VERSION 5.8 ;
BUSBITCHARS "[]" ;
DIVIDERCHAR "/" ;
UNITS
    DATABASE MICRONS 1000 ;
END UNITS

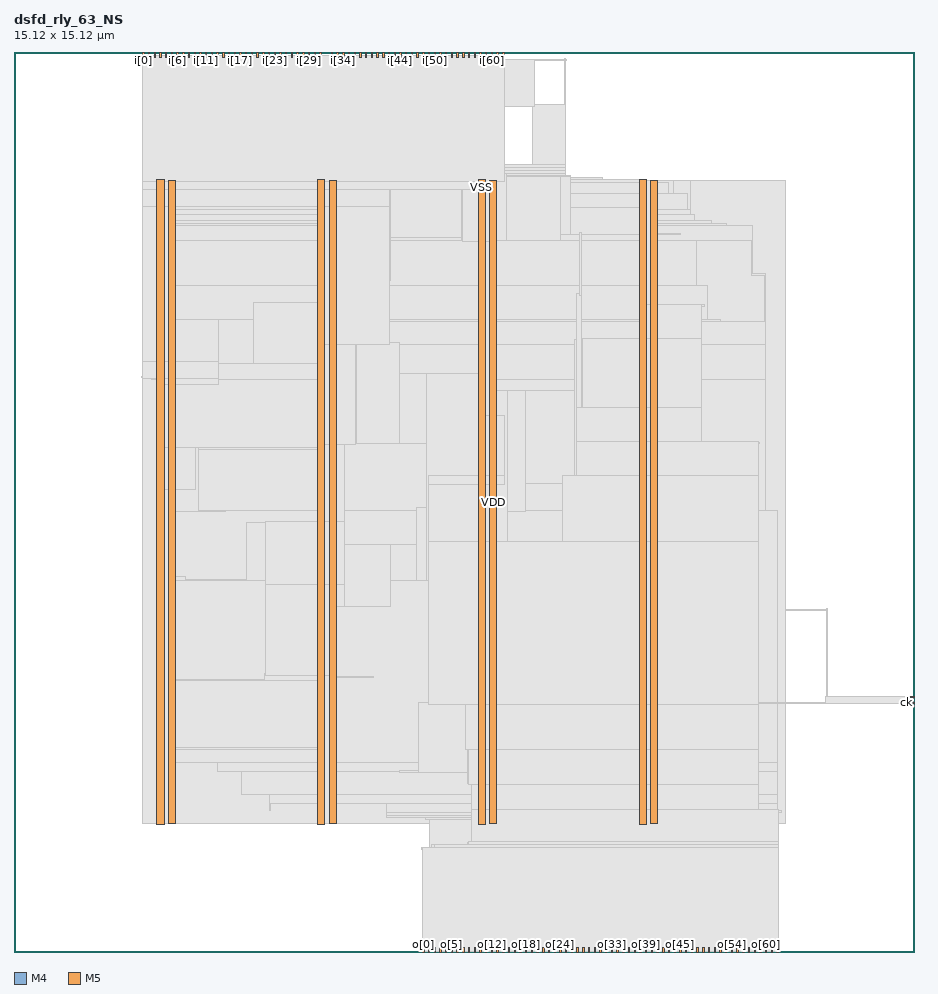
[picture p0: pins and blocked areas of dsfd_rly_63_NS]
MACRO dsfd_rly_63_NS
  FOREIGN dsfd_rly_63_NS 0 0 ;
  CLASS BLOCK ;
  SIZE 15.12 BY 15.12 ;
  PIN ck
    DIRECTION INPUT ;
    USE SIGNAL ;
    PORT
      LAYER M4 ;
        RECT  15.036 4.176 15.12 4.2 ;
    END
  END ck
  PIN i[0]
    DIRECTION INPUT ;
    USE SIGNAL ;
    PORT
      LAYER M5 ;
        RECT  2.16 15.036 2.184 15.12 ;
    END
  END i[0]
  PIN i[10]
    DIRECTION INPUT ;
    USE SIGNAL ;
    PORT
      LAYER M5 ;
        RECT  3.12 15.036 3.144 15.12 ;
    END
  END i[10]
  PIN i[11]
    DIRECTION INPUT ;
    USE SIGNAL ;
    PORT
      LAYER M5 ;
        RECT  3.216 15.036 3.24 15.12 ;
    END
  END i[11]
  PIN i[12]
    DIRECTION INPUT ;
    USE SIGNAL ;
    PORT
      LAYER M5 ;
        RECT  3.312 15.036 3.336 15.12 ;
    END
  END i[12]
  PIN i[13]
    DIRECTION INPUT ;
    USE SIGNAL ;
    PORT
      LAYER M5 ;
        RECT  3.408 15.036 3.432 15.12 ;
    END
  END i[13]
  PIN i[14]
    DIRECTION INPUT ;
    USE SIGNAL ;
    PORT
      LAYER M5 ;
        RECT  3.504 15.036 3.528 15.12 ;
    END
  END i[14]
  PIN i[15]
    DIRECTION INPUT ;
    USE SIGNAL ;
    PORT
      LAYER M5 ;
        RECT  3.6 15.036 3.624 15.12 ;
    END
  END i[15]
  PIN i[16]
    DIRECTION INPUT ;
    USE SIGNAL ;
    PORT
      LAYER M5 ;
        RECT  3.696 15.036 3.72 15.12 ;
    END
  END i[16]
  PIN i[17]
    DIRECTION INPUT ;
    USE SIGNAL ;
    PORT
      LAYER M5 ;
        RECT  3.792 15.036 3.816 15.12 ;
    END
  END i[17]
  PIN i[18]
    DIRECTION INPUT ;
    USE SIGNAL ;
    PORT
      LAYER M5 ;
        RECT  3.888 15.036 3.912 15.12 ;
    END
  END i[18]
  PIN i[19]
    DIRECTION INPUT ;
    USE SIGNAL ;
    PORT
      LAYER M5 ;
        RECT  3.984 15.036 4.008 15.12 ;
    END
  END i[19]
  PIN i[1]
    DIRECTION INPUT ;
    USE SIGNAL ;
    PORT
      LAYER M5 ;
        RECT  2.256 15.036 2.28 15.12 ;
    END
  END i[1]
  PIN i[20]
    DIRECTION INPUT ;
    USE SIGNAL ;
    PORT
      LAYER M5 ;
        RECT  4.08 15.036 4.104 15.12 ;
    END
  END i[20]
  PIN i[21]
    DIRECTION INPUT ;
    USE SIGNAL ;
    PORT
      LAYER M5 ;
        RECT  4.176 15.036 4.2 15.12 ;
    END
  END i[21]
  PIN i[22]
    DIRECTION INPUT ;
    USE SIGNAL ;
    PORT
      LAYER M5 ;
        RECT  4.272 15.036 4.296 15.12 ;
    END
  END i[22]
  PIN i[23]
    DIRECTION INPUT ;
    USE SIGNAL ;
    PORT
      LAYER M5 ;
        RECT  4.368 15.036 4.392 15.12 ;
    END
  END i[23]
  PIN i[24]
    DIRECTION INPUT ;
    USE SIGNAL ;
    PORT
      LAYER M5 ;
        RECT  4.464 15.036 4.488 15.12 ;
    END
  END i[24]
  PIN i[25]
    DIRECTION INPUT ;
    USE SIGNAL ;
    PORT
      LAYER M5 ;
        RECT  4.56 15.036 4.584 15.12 ;
    END
  END i[25]
  PIN i[26]
    DIRECTION INPUT ;
    USE SIGNAL ;
    PORT
      LAYER M5 ;
        RECT  4.656 15.036 4.68 15.12 ;
    END
  END i[26]
  PIN i[27]
    DIRECTION INPUT ;
    USE SIGNAL ;
    PORT
      LAYER M5 ;
        RECT  4.752 15.036 4.776 15.12 ;
    END
  END i[27]
  PIN i[28]
    DIRECTION INPUT ;
    USE SIGNAL ;
    PORT
      LAYER M5 ;
        RECT  4.848 15.036 4.872 15.12 ;
    END
  END i[28]
  PIN i[29]
    DIRECTION INPUT ;
    USE SIGNAL ;
    PORT
      LAYER M5 ;
        RECT  4.944 15.036 4.968 15.12 ;
    END
  END i[29]
  PIN i[2]
    DIRECTION INPUT ;
    USE SIGNAL ;
    PORT
      LAYER M5 ;
        RECT  2.352 15.036 2.376 15.12 ;
    END
  END i[2]
  PIN i[30]
    DIRECTION INPUT ;
    USE SIGNAL ;
    PORT
      LAYER M5 ;
        RECT  5.04 15.036 5.064 15.12 ;
    END
  END i[30]
  PIN i[31]
    DIRECTION INPUT ;
    USE SIGNAL ;
    PORT
      LAYER M5 ;
        RECT  5.136 15.036 5.16 15.12 ;
    END
  END i[31]
  PIN i[32]
    DIRECTION INPUT ;
    USE SIGNAL ;
    PORT
      LAYER M5 ;
        RECT  5.328 15.036 5.352 15.12 ;
    END
  END i[32]
  PIN i[33]
    DIRECTION INPUT ;
    USE SIGNAL ;
    PORT
      LAYER M5 ;
        RECT  5.424 15.036 5.448 15.12 ;
    END
  END i[33]
  PIN i[34]
    DIRECTION INPUT ;
    USE SIGNAL ;
    PORT
      LAYER M5 ;
        RECT  5.52 15.036 5.544 15.12 ;
    END
  END i[34]
  PIN i[35]
    DIRECTION INPUT ;
    USE SIGNAL ;
    PORT
      LAYER M5 ;
        RECT  5.616 15.036 5.64 15.12 ;
    END
  END i[35]
  PIN i[36]
    DIRECTION INPUT ;
    USE SIGNAL ;
    PORT
      LAYER M5 ;
        RECT  5.712 15.036 5.736 15.12 ;
    END
  END i[36]
  PIN i[37]
    DIRECTION INPUT ;
    USE SIGNAL ;
    PORT
      LAYER M5 ;
        RECT  5.808 15.036 5.832 15.12 ;
    END
  END i[37]
  PIN i[38]
    DIRECTION INPUT ;
    USE SIGNAL ;
    PORT
      LAYER M5 ;
        RECT  5.904 15.036 5.928 15.12 ;
    END
  END i[38]
  PIN i[39]
    DIRECTION INPUT ;
    USE SIGNAL ;
    PORT
      LAYER M5 ;
        RECT  6 15.036 6.024 15.12 ;
    END
  END i[39]
  PIN i[3]
    DIRECTION INPUT ;
    USE SIGNAL ;
    PORT
      LAYER M5 ;
        RECT  2.448 15.036 2.472 15.12 ;
    END
  END i[3]
  PIN i[40]
    DIRECTION INPUT ;
    USE SIGNAL ;
    PORT
      LAYER M5 ;
        RECT  6.096 15.036 6.12 15.12 ;
    END
  END i[40]
  PIN i[41]
    DIRECTION INPUT ;
    USE SIGNAL ;
    PORT
      LAYER M5 ;
        RECT  6.192 15.036 6.216 15.12 ;
    END
  END i[41]
  PIN i[42]
    DIRECTION INPUT ;
    USE SIGNAL ;
    PORT
      LAYER M5 ;
        RECT  6.288 15.036 6.312 15.12 ;
    END
  END i[42]
  PIN i[43]
    DIRECTION INPUT ;
    USE SIGNAL ;
    PORT
      LAYER M5 ;
        RECT  6.384 15.036 6.408 15.12 ;
    END
  END i[43]
  PIN i[44]
    DIRECTION INPUT ;
    USE SIGNAL ;
    PORT
      LAYER M5 ;
        RECT  6.48 15.036 6.504 15.12 ;
    END
  END i[44]
  PIN i[45]
    DIRECTION INPUT ;
    USE SIGNAL ;
    PORT
      LAYER M5 ;
        RECT  6.576 15.036 6.6 15.12 ;
    END
  END i[45]
  PIN i[46]
    DIRECTION INPUT ;
    USE SIGNAL ;
    PORT
      LAYER M5 ;
        RECT  6.672 15.036 6.696 15.12 ;
    END
  END i[46]
  PIN i[47]
    DIRECTION INPUT ;
    USE SIGNAL ;
    PORT
      LAYER M5 ;
        RECT  6.768 15.036 6.792 15.12 ;
    END
  END i[47]
  PIN i[48]
    DIRECTION INPUT ;
    USE SIGNAL ;
    PORT
      LAYER M5 ;
        RECT  6.864 15.036 6.888 15.12 ;
    END
  END i[48]
  PIN i[49]
    DIRECTION INPUT ;
    USE SIGNAL ;
    PORT
      LAYER M5 ;
        RECT  6.96 15.036 6.984 15.12 ;
    END
  END i[49]
  PIN i[4]
    DIRECTION INPUT ;
    USE SIGNAL ;
    PORT
      LAYER M5 ;
        RECT  2.544 15.036 2.568 15.12 ;
    END
  END i[4]
  PIN i[50]
    DIRECTION INPUT ;
    USE SIGNAL ;
    PORT
      LAYER M5 ;
        RECT  7.056 15.036 7.08 15.12 ;
    END
  END i[50]
  PIN i[51]
    DIRECTION INPUT ;
    USE SIGNAL ;
    PORT
      LAYER M5 ;
        RECT  7.152 15.036 7.176 15.12 ;
    END
  END i[51]
  PIN i[52]
    DIRECTION INPUT ;
    USE SIGNAL ;
    PORT
      LAYER M5 ;
        RECT  7.248 15.036 7.272 15.12 ;
    END
  END i[52]
  PIN i[53]
    DIRECTION INPUT ;
    USE SIGNAL ;
    PORT
      LAYER M5 ;
        RECT  7.344 15.036 7.368 15.12 ;
    END
  END i[53]
  PIN i[54]
    DIRECTION INPUT ;
    USE SIGNAL ;
    PORT
      LAYER M5 ;
        RECT  7.44 15.036 7.464 15.12 ;
    END
  END i[54]
  PIN i[55]
    DIRECTION INPUT ;
    USE SIGNAL ;
    PORT
      LAYER M5 ;
        RECT  7.536 15.036 7.56 15.12 ;
    END
  END i[55]
  PIN i[56]
    DIRECTION INPUT ;
    USE SIGNAL ;
    PORT
      LAYER M5 ;
        RECT  7.632 15.036 7.656 15.12 ;
    END
  END i[56]
  PIN i[57]
    DIRECTION INPUT ;
    USE SIGNAL ;
    PORT
      LAYER M5 ;
        RECT  7.728 15.036 7.752 15.12 ;
    END
  END i[57]
  PIN i[58]
    DIRECTION INPUT ;
    USE SIGNAL ;
    PORT
      LAYER M5 ;
        RECT  7.824 15.036 7.848 15.12 ;
    END
  END i[58]
  PIN i[59]
    DIRECTION INPUT ;
    USE SIGNAL ;
    PORT
      LAYER M5 ;
        RECT  7.92 15.036 7.944 15.12 ;
    END
  END i[59]
  PIN i[5]
    DIRECTION INPUT ;
    USE SIGNAL ;
    PORT
      LAYER M5 ;
        RECT  2.64 15.036 2.664 15.12 ;
    END
  END i[5]
  PIN i[60]
    DIRECTION INPUT ;
    USE SIGNAL ;
    PORT
      LAYER M5 ;
        RECT  8.016 15.036 8.04 15.12 ;
    END
  END i[60]
  PIN i[61]
    DIRECTION INPUT ;
    USE SIGNAL ;
    PORT
      LAYER M5 ;
        RECT  8.112 15.036 8.136 15.12 ;
    END
  END i[61]
  PIN i[62]
    DIRECTION INPUT ;
    USE SIGNAL ;
    PORT
      LAYER M5 ;
        RECT  8.208 15.036 8.232 15.12 ;
    END
  END i[62]
  PIN i[6]
    DIRECTION INPUT ;
    USE SIGNAL ;
    PORT
      LAYER M5 ;
        RECT  2.736 15.036 2.76 15.12 ;
    END
  END i[6]
  PIN i[7]
    DIRECTION INPUT ;
    USE SIGNAL ;
    PORT
      LAYER M5 ;
        RECT  2.832 15.036 2.856 15.12 ;
    END
  END i[7]
  PIN i[8]
    DIRECTION INPUT ;
    USE SIGNAL ;
    PORT
      LAYER M5 ;
        RECT  2.928 15.036 2.952 15.12 ;
    END
  END i[8]
  PIN i[9]
    DIRECTION INPUT ;
    USE SIGNAL ;
    PORT
      LAYER M5 ;
        RECT  3.024 15.036 3.048 15.12 ;
    END
  END i[9]
  PIN o[0]
    DIRECTION OUTPUT ;
    USE SIGNAL ;
    PORT
      LAYER M5 ;
        RECT  6.864 0 6.888 0.084 ;
    END
  END o[0]
  PIN o[10]
    DIRECTION OUTPUT ;
    USE SIGNAL ;
    PORT
      LAYER M5 ;
        RECT  7.824 0 7.848 0.084 ;
    END
  END o[10]
  PIN o[11]
    DIRECTION OUTPUT ;
    USE SIGNAL ;
    PORT
      LAYER M5 ;
        RECT  7.92 0 7.944 0.084 ;
    END
  END o[11]
  PIN o[12]
    DIRECTION OUTPUT ;
    USE SIGNAL ;
    PORT
      LAYER M5 ;
        RECT  8.016 0 8.04 0.084 ;
    END
  END o[12]
  PIN o[13]
    DIRECTION OUTPUT ;
    USE SIGNAL ;
    PORT
      LAYER M5 ;
        RECT  8.112 0 8.136 0.084 ;
    END
  END o[13]
  PIN o[14]
    DIRECTION OUTPUT ;
    USE SIGNAL ;
    PORT
      LAYER M5 ;
        RECT  8.208 0 8.232 0.084 ;
    END
  END o[14]
  PIN o[15]
    DIRECTION OUTPUT ;
    USE SIGNAL ;
    PORT
      LAYER M5 ;
        RECT  8.304 0 8.328 0.084 ;
    END
  END o[15]
  PIN o[16]
    DIRECTION OUTPUT ;
    USE SIGNAL ;
    PORT
      LAYER M5 ;
        RECT  8.4 0 8.424 0.084 ;
    END
  END o[16]
  PIN o[17]
    DIRECTION OUTPUT ;
    USE SIGNAL ;
    PORT
      LAYER M5 ;
        RECT  8.496 0 8.52 0.084 ;
    END
  END o[17]
  PIN o[18]
    DIRECTION OUTPUT ;
    USE SIGNAL ;
    PORT
      LAYER M5 ;
        RECT  8.592 0 8.616 0.084 ;
    END
  END o[18]
  PIN o[19]
    DIRECTION OUTPUT ;
    USE SIGNAL ;
    PORT
      LAYER M5 ;
        RECT  8.688 0 8.712 0.084 ;
    END
  END o[19]
  PIN o[1]
    DIRECTION OUTPUT ;
    USE SIGNAL ;
    PORT
      LAYER M5 ;
        RECT  6.96 0 6.984 0.084 ;
    END
  END o[1]
  PIN o[20]
    DIRECTION OUTPUT ;
    USE SIGNAL ;
    PORT
      LAYER M5 ;
        RECT  8.784 0 8.808 0.084 ;
    END
  END o[20]
  PIN o[21]
    DIRECTION OUTPUT ;
    USE SIGNAL ;
    PORT
      LAYER M5 ;
        RECT  8.88 0 8.904 0.084 ;
    END
  END o[21]
  PIN o[22]
    DIRECTION OUTPUT ;
    USE SIGNAL ;
    PORT
      LAYER M5 ;
        RECT  8.976 0 9 0.084 ;
    END
  END o[22]
  PIN o[23]
    DIRECTION OUTPUT ;
    USE SIGNAL ;
    PORT
      LAYER M5 ;
        RECT  9.072 0 9.096 0.084 ;
    END
  END o[23]
  PIN o[24]
    DIRECTION OUTPUT ;
    USE SIGNAL ;
    PORT
      LAYER M5 ;
        RECT  9.168 0 9.192 0.084 ;
    END
  END o[24]
  PIN o[25]
    DIRECTION OUTPUT ;
    USE SIGNAL ;
    PORT
      LAYER M5 ;
        RECT  9.264 0 9.288 0.084 ;
    END
  END o[25]
  PIN o[26]
    DIRECTION OUTPUT ;
    USE SIGNAL ;
    PORT
      LAYER M5 ;
        RECT  9.36 0 9.384 0.084 ;
    END
  END o[26]
  PIN o[27]
    DIRECTION OUTPUT ;
    USE SIGNAL ;
    PORT
      LAYER M5 ;
        RECT  9.456 0 9.48 0.084 ;
    END
  END o[27]
  PIN o[28]
    DIRECTION OUTPUT ;
    USE SIGNAL ;
    PORT
      LAYER M5 ;
        RECT  9.552 0 9.576 0.084 ;
    END
  END o[28]
  PIN o[29]
    DIRECTION OUTPUT ;
    USE SIGNAL ;
    PORT
      LAYER M5 ;
        RECT  9.648 0 9.672 0.084 ;
    END
  END o[29]
  PIN o[2]
    DIRECTION OUTPUT ;
    USE SIGNAL ;
    PORT
      LAYER M5 ;
        RECT  7.056 0 7.08 0.084 ;
    END
  END o[2]
  PIN o[30]
    DIRECTION OUTPUT ;
    USE SIGNAL ;
    PORT
      LAYER M5 ;
        RECT  9.744 0 9.768 0.084 ;
    END
  END o[30]
  PIN o[31]
    DIRECTION OUTPUT ;
    USE SIGNAL ;
    PORT
      LAYER M5 ;
        RECT  9.84 0 9.864 0.084 ;
    END
  END o[31]
  PIN o[32]
    DIRECTION OUTPUT ;
    USE SIGNAL ;
    PORT
      LAYER M5 ;
        RECT  9.936 0 9.96 0.084 ;
    END
  END o[32]
  PIN o[33]
    DIRECTION OUTPUT ;
    USE SIGNAL ;
    PORT
      LAYER M5 ;
        RECT  10.032 0 10.056 0.084 ;
    END
  END o[33]
  PIN o[34]
    DIRECTION OUTPUT ;
    USE SIGNAL ;
    PORT
      LAYER M5 ;
        RECT  10.128 0 10.152 0.084 ;
    END
  END o[34]
  PIN o[35]
    DIRECTION OUTPUT ;
    USE SIGNAL ;
    PORT
      LAYER M5 ;
        RECT  10.224 0 10.248 0.084 ;
    END
  END o[35]
  PIN o[36]
    DIRECTION OUTPUT ;
    USE SIGNAL ;
    PORT
      LAYER M5 ;
        RECT  10.32 0 10.344 0.084 ;
    END
  END o[36]
  PIN o[37]
    DIRECTION OUTPUT ;
    USE SIGNAL ;
    PORT
      LAYER M5 ;
        RECT  10.416 0 10.44 0.084 ;
    END
  END o[37]
  PIN o[38]
    DIRECTION OUTPUT ;
    USE SIGNAL ;
    PORT
      LAYER M5 ;
        RECT  10.512 0 10.536 0.084 ;
    END
  END o[38]
  PIN o[39]
    DIRECTION OUTPUT ;
    USE SIGNAL ;
    PORT
      LAYER M5 ;
        RECT  10.608 0 10.632 0.084 ;
    END
  END o[39]
  PIN o[3]
    DIRECTION OUTPUT ;
    USE SIGNAL ;
    PORT
      LAYER M5 ;
        RECT  7.152 0 7.176 0.084 ;
    END
  END o[3]
  PIN o[40]
    DIRECTION OUTPUT ;
    USE SIGNAL ;
    PORT
      LAYER M5 ;
        RECT  10.704 0 10.728 0.084 ;
    END
  END o[40]
  PIN o[41]
    DIRECTION OUTPUT ;
    USE SIGNAL ;
    PORT
      LAYER M5 ;
        RECT  10.8 0 10.824 0.084 ;
    END
  END o[41]
  PIN o[42]
    DIRECTION OUTPUT ;
    USE SIGNAL ;
    PORT
      LAYER M5 ;
        RECT  10.896 0 10.92 0.084 ;
    END
  END o[42]
  PIN o[43]
    DIRECTION OUTPUT ;
    USE SIGNAL ;
    PORT
      LAYER M5 ;
        RECT  10.992 0 11.016 0.084 ;
    END
  END o[43]
  PIN o[44]
    DIRECTION OUTPUT ;
    USE SIGNAL ;
    PORT
      LAYER M5 ;
        RECT  11.088 0 11.112 0.084 ;
    END
  END o[44]
  PIN o[45]
    DIRECTION OUTPUT ;
    USE SIGNAL ;
    PORT
      LAYER M5 ;
        RECT  11.184 0 11.208 0.084 ;
    END
  END o[45]
  PIN o[46]
    DIRECTION OUTPUT ;
    USE SIGNAL ;
    PORT
      LAYER M5 ;
        RECT  11.28 0 11.304 0.084 ;
    END
  END o[46]
  PIN o[47]
    DIRECTION OUTPUT ;
    USE SIGNAL ;
    PORT
      LAYER M5 ;
        RECT  11.376 0 11.4 0.084 ;
    END
  END o[47]
  PIN o[48]
    DIRECTION OUTPUT ;
    USE SIGNAL ;
    PORT
      LAYER M5 ;
        RECT  11.472 0 11.496 0.084 ;
    END
  END o[48]
  PIN o[49]
    DIRECTION OUTPUT ;
    USE SIGNAL ;
    PORT
      LAYER M5 ;
        RECT  11.568 0 11.592 0.084 ;
    END
  END o[49]
  PIN o[4]
    DIRECTION OUTPUT ;
    USE SIGNAL ;
    PORT
      LAYER M5 ;
        RECT  7.248 0 7.272 0.084 ;
    END
  END o[4]
  PIN o[50]
    DIRECTION OUTPUT ;
    USE SIGNAL ;
    PORT
      LAYER M5 ;
        RECT  11.664 0 11.688 0.084 ;
    END
  END o[50]
  PIN o[51]
    DIRECTION OUTPUT ;
    USE SIGNAL ;
    PORT
      LAYER M5 ;
        RECT  11.76 0 11.784 0.084 ;
    END
  END o[51]
  PIN o[52]
    DIRECTION OUTPUT ;
    USE SIGNAL ;
    PORT
      LAYER M5 ;
        RECT  11.856 0 11.88 0.084 ;
    END
  END o[52]
  PIN o[53]
    DIRECTION OUTPUT ;
    USE SIGNAL ;
    PORT
      LAYER M5 ;
        RECT  11.952 0 11.976 0.084 ;
    END
  END o[53]
  PIN o[54]
    DIRECTION OUTPUT ;
    USE SIGNAL ;
    PORT
      LAYER M5 ;
        RECT  12.048 0 12.072 0.084 ;
    END
  END o[54]
  PIN o[55]
    DIRECTION OUTPUT ;
    USE SIGNAL ;
    PORT
      LAYER M5 ;
        RECT  12.144 0 12.168 0.084 ;
    END
  END o[55]
  PIN o[56]
    DIRECTION OUTPUT ;
    USE SIGNAL ;
    PORT
      LAYER M5 ;
        RECT  12.24 0 12.264 0.084 ;
    END
  END o[56]
  PIN o[57]
    DIRECTION OUTPUT ;
    USE SIGNAL ;
    PORT
      LAYER M5 ;
        RECT  12.336 0 12.36 0.084 ;
    END
  END o[57]
  PIN o[58]
    DIRECTION OUTPUT ;
    USE SIGNAL ;
    PORT
      LAYER M5 ;
        RECT  12.432 0 12.456 0.084 ;
    END
  END o[58]
  PIN o[59]
    DIRECTION OUTPUT ;
    USE SIGNAL ;
    PORT
      LAYER M5 ;
        RECT  12.528 0 12.552 0.084 ;
    END
  END o[59]
  PIN o[5]
    DIRECTION OUTPUT ;
    USE SIGNAL ;
    PORT
      LAYER M5 ;
        RECT  7.344 0 7.368 0.084 ;
    END
  END o[5]
  PIN o[60]
    DIRECTION OUTPUT ;
    USE SIGNAL ;
    PORT
      LAYER M5 ;
        RECT  12.624 0 12.648 0.084 ;
    END
  END o[60]
  PIN o[61]
    DIRECTION OUTPUT ;
    USE SIGNAL ;
    PORT
      LAYER M5 ;
        RECT  12.72 0 12.744 0.084 ;
    END
  END o[61]
  PIN o[62]
    DIRECTION OUTPUT ;
    USE SIGNAL ;
    PORT
      LAYER M5 ;
        RECT  12.816 0 12.84 0.084 ;
    END
  END o[62]
  PIN o[6]
    DIRECTION OUTPUT ;
    USE SIGNAL ;
    PORT
      LAYER M5 ;
        RECT  7.44 0 7.464 0.084 ;
    END
  END o[6]
  PIN o[7]
    DIRECTION OUTPUT ;
    USE SIGNAL ;
    PORT
      LAYER M5 ;
        RECT  7.536 0 7.56 0.084 ;
    END
  END o[7]
  PIN o[8]
    DIRECTION OUTPUT ;
    USE SIGNAL ;
    PORT
      LAYER M5 ;
        RECT  7.632 0 7.656 0.084 ;
    END
  END o[8]
  PIN o[9]
    DIRECTION OUTPUT ;
    USE SIGNAL ;
    PORT
      LAYER M5 ;
        RECT  7.728 0 7.752 0.084 ;
    END
  END o[9]
  PIN rs
    DIRECTION INPUT ;
    USE SIGNAL ;
    PORT
      LAYER M4 ;
        RECT  15.036 4.272 15.12 4.296 ;
    END
  END rs
  PIN VDD
    DIRECTION INOUT ;
    USE POWER ;
    PORT
      LAYER M5 ;
        RECT  10.692 2.151 10.812 12.969 ;
        RECT  7.992 2.151 8.112 12.969 ;
        RECT  5.292 2.151 5.412 12.969 ;
        RECT  2.592 2.151 2.712 12.969 ;
    END
  END VDD
  PIN VSS
    DIRECTION INOUT ;
    USE GROUND ;
    PORT
      LAYER M5 ;
        RECT  10.5 2.137 10.62 12.983 ;
        RECT  7.8 2.137 7.92 12.983 ;
        RECT  5.1 2.137 5.22 12.983 ;
        RECT  2.4 2.137 2.52 12.983 ;
    END
  END VSS
  OBS
    LAYER RVTN ;
     RECT  2.16 2.16 12.96 2.295 ;
     RECT  2.16 2.565 12.96 2.835 ;
     RECT  2.16 3.105 12.96 3.375 ;
     RECT  2.16 3.645 12.96 3.915 ;
     RECT  2.16 4.185 12.96 4.455 ;
     RECT  2.16 4.725 12.96 4.995 ;
     RECT  2.16 5.265 12.96 5.535 ;
     RECT  2.16 5.805 12.96 6.075 ;
     RECT  2.16 6.345 12.96 6.615 ;
     RECT  2.16 6.885 12.96 7.155 ;
     RECT  2.16 7.425 12.96 7.695 ;
     RECT  2.16 7.965 12.96 8.235 ;
     RECT  2.16 8.505 12.96 8.775 ;
     RECT  2.16 9.045 12.96 9.315 ;
     RECT  2.16 9.585 12.96 9.855 ;
     RECT  2.16 10.125 12.96 10.395 ;
     RECT  2.16 10.665 12.96 10.935 ;
     RECT  2.16 11.205 12.96 11.475 ;
     RECT  2.16 11.745 12.96 12.015 ;
     RECT  2.16 12.285 12.96 12.555 ;
     RECT  2.16 12.825 12.96 12.96 ;
    LAYER RVTP ;
     RECT  2.16 2.295 12.96 2.565 ;
     RECT  2.16 2.835 12.96 3.105 ;
     RECT  2.16 3.375 12.96 3.645 ;
     RECT  2.16 3.915 12.96 4.185 ;
     RECT  2.16 4.455 12.96 4.725 ;
     RECT  2.16 4.995 12.96 5.265 ;
     RECT  2.16 5.535 12.96 5.805 ;
     RECT  2.16 6.075 12.96 6.345 ;
     RECT  2.16 6.615 12.96 6.885 ;
     RECT  2.16 7.155 12.96 7.425 ;
     RECT  2.16 7.695 12.96 7.965 ;
     RECT  2.16 8.235 12.96 8.505 ;
     RECT  2.16 8.775 12.96 9.045 ;
     RECT  2.16 9.315 12.96 9.585 ;
     RECT  2.16 9.855 12.96 10.125 ;
     RECT  2.16 10.395 12.96 10.665 ;
     RECT  2.16 10.935 12.96 11.205 ;
     RECT  2.16 11.475 12.96 11.745 ;
     RECT  2.16 12.015 12.96 12.285 ;
     RECT  2.16 12.555 12.96 12.825 ;
    LAYER M1 ;
     RECT  2.16 2.151 12.96 12.969 ;
    LAYER M2 ;
     RECT  2.16 2.151 8.959 12.969 ;
     RECT  8.959 2.151 9.887 13.014 ;
     RECT  9.887 2.151 11.083 12.969 ;
     RECT  11.083 2.106 11.363 12.969 ;
     RECT  11.363 2.151 12.96 12.969 ;
     RECT  12.96 5.742 13.667 5.76 ;
    LAYER M3 ;
     RECT  8.136 0.091 8.154 0.139 ;
     RECT  9.144 0.091 9.162 0.139 ;
     RECT  12.06 0.091 12.474 0.139 ;
     RECT  8.136 0.139 9.162 0.235 ;
     RECT  6.984 0.091 7.002 0.475 ;
     RECT  7.74 0.235 9.162 0.475 ;
     RECT  6.984 0.475 9.162 0.523 ;
     RECT  10.332 0.427 10.35 0.523 ;
     RECT  10.332 0.523 10.494 0.571 ;
     RECT  10.332 0.571 10.962 0.619 ;
     RECT  10.332 0.619 11.07 1.099 ;
     RECT  12.06 0.139 12.726 1.099 ;
     RECT  6.984 0.523 9.45 1.147 ;
     RECT  10.332 1.099 12.726 1.147 ;
     RECT  6.984 1.147 12.726 2.227 ;
     RECT  6.912 2.227 12.726 2.263 ;
     RECT  6.264 2.263 12.726 2.299 ;
     RECT  6.264 2.299 12.762 2.347 ;
     RECT  2.415 2.143 2.505 2.413 ;
     RECT  5.115 2.143 5.205 2.413 ;
     RECT  4.284 2.371 4.302 2.497 ;
     RECT  5.115 2.413 5.397 2.497 ;
     RECT  6.264 2.347 12.834 2.497 ;
     RECT  4.284 2.497 12.834 2.641 ;
     RECT  3.816 2.641 12.834 3.037 ;
     RECT  2.415 2.413 2.697 3.181 ;
     RECT  3.42 3.037 12.834 3.181 ;
     RECT  13.644 4.267 13.662 5.765 ;
     RECT  2.415 3.181 12.834 7.421 ;
     RECT  2.415 7.421 12.618 9.625 ;
     RECT  2.304 9.625 12.618 10.205 ;
     RECT  2.34 10.205 12.618 10.589 ;
     RECT  2.34 10.589 11.862 10.625 ;
     RECT  2.34 10.625 11.646 11.201 ;
     RECT  12.6 10.589 12.618 11.371 ;
     RECT  12.384 11.371 12.618 11.399 ;
     RECT  2.34 11.201 11.466 11.947 ;
     RECT  12.384 11.399 12.402 11.947 ;
     RECT  2.34 11.947 12.402 12.209 ;
     RECT  2.34 12.209 11.97 12.245 ;
     RECT  2.34 12.245 11.718 12.281 ;
     RECT  2.34 12.281 11.43 12.389 ;
     RECT  2.34 12.389 11.358 12.479 ;
     RECT  2.34 12.479 11.322 12.749 ;
     RECT  2.34 12.749 10.998 12.929 ;
     RECT  2.34 12.929 10.605 12.977 ;
     RECT  2.34 12.977 9.882 13.019 ;
     RECT  2.34 13.019 9.342 13.037 ;
     RECT  2.34 13.037 9.27 13.085 ;
     RECT  2.34 13.085 3.078 13.133 ;
     RECT  5.076 13.085 5.454 13.133 ;
     RECT  7.74 13.085 9.27 13.133 ;
     RECT  5.256 13.133 5.274 13.181 ;
     RECT  7.956 13.133 9.27 13.181 ;
     RECT  2.376 13.133 3.078 13.229 ;
     RECT  8.064 13.181 9.27 13.229 ;
     RECT  8.712 13.229 9.27 14.237 ;
     RECT  3.06 13.229 3.078 15.005 ;
     RECT  9.252 14.237 9.27 15.005 ;
    LAYER M4 ;
     RECT  2.149 9.648 2.245 9.672 ;
     RECT  2.3 13.104 2.365 13.128 ;
     RECT  2.245 9.648 2.408 10.2 ;
     RECT  2.365 13.104 2.408 13.224 ;
     RECT  2.408 2.148 2.512 13.224 ;
     RECT  2.512 2.418 2.579 13.224 ;
     RECT  2.579 2.418 2.585 13.128 ;
     RECT  2.585 2.418 2.704 13.08 ;
     RECT  2.704 6.24 2.873 6.312 ;
     RECT  2.629 14.976 3.089 15 ;
     RECT  2.704 7.392 3.1 8.472 ;
     RECT  2.704 9.552 3.443 10.632 ;
     RECT  3.1 7.392 3.557 7.416 ;
     RECT  2.873 6.24 3.913 6.264 ;
     RECT  3.443 9.888 4.021 10.632 ;
     RECT  2.704 4.56 4.213 4.584 ;
     RECT  2.704 12.528 5.021 13.08 ;
     RECT  5.021 12.528 5.104 13.128 ;
     RECT  2.704 3.408 5.108 3.432 ;
     RECT  4.213 4.56 5.108 4.68 ;
     RECT  3.913 6.24 5.108 7.224 ;
     RECT  3.1 8.448 5.108 8.472 ;
     RECT  4.021 9.888 5.108 10.92 ;
     RECT  5.104 12.528 5.108 13.176 ;
     RECT  5.108 2.148 5.212 13.176 ;
     RECT  5.212 2.418 5.285 13.176 ;
     RECT  5.285 2.418 5.404 13.128 ;
     RECT  5.404 8.544 5.465 13.128 ;
     RECT  5.404 5.808 5.555 7.224 ;
     RECT  5.465 8.544 5.753 13.08 ;
     RECT  5.404 4.608 6.041 4.632 ;
     RECT  5.753 11.28 6.323 13.08 ;
     RECT  5.555 5.808 6.329 6.84 ;
     RECT  5.753 8.544 6.473 10.248 ;
     RECT  6.329 6.24 6.757 6.84 ;
     RECT  6.469 3.024 6.793 3.048 ;
     RECT  6.757 6.24 6.937 7.464 ;
     RECT  6.473 8.544 6.937 9.72 ;
     RECT  6.853 1.728 7.009 1.752 ;
     RECT  6.929 0.096 7.013 0.12 ;
     RECT  7.081 0.144 7.379 0.552 ;
     RECT  6.323 12 7.525 13.08 ;
     RECT  7.009 1.728 7.621 1.8 ;
     RECT  6.793 3.024 7.621 4.2 ;
     RECT  7.525 11.952 7.685 13.08 ;
     RECT  7.621 1.728 7.765 1.848 ;
     RECT  7.379 0.144 7.769 0.264 ;
     RECT  7.765 1.68 7.808 1.848 ;
     RECT  7.621 2.832 7.808 4.2 ;
     RECT  6.937 6.24 7.808 9.72 ;
     RECT  7.685 11.952 7.808 13.128 ;
     RECT  7.808 1.68 7.813 13.128 ;
     RECT  7.813 1.68 7.859 13.176 ;
     RECT  7.859 1.728 7.984 13.176 ;
     RECT  7.769 0.144 8.005 0.168 ;
     RECT  7.984 1.728 8.093 13.224 ;
     RECT  7.237 14.208 8.101 14.232 ;
     RECT  8.093 1.728 8.104 13.08 ;
     RECT  8.104 11.952 8.273 13.08 ;
     RECT  8.104 6.096 8.291 9.432 ;
     RECT  8.291 7.392 8.597 9.432 ;
     RECT  8.101 14.208 8.741 15 ;
     RECT  8.005 0.096 9.173 0.168 ;
     RECT  8.273 11.952 9.173 13.032 ;
     RECT  8.104 1.728 9.233 3.048 ;
     RECT  8.104 4.176 9.233 4.2 ;
     RECT  8.741 14.976 9.281 15 ;
     RECT  9.173 12.048 9.353 13.032 ;
     RECT  8.597 7.872 9.421 9.432 ;
     RECT  9.421 7.872 9.452 10.296 ;
     RECT  9.452 7.872 9.539 11.064 ;
     RECT  9.421 0.528 9.829 0.552 ;
     RECT  9.233 1.728 9.829 4.2 ;
     RECT  8.291 6.096 9.925 6.408 ;
     RECT  9.925 6.096 10.021 6.888 ;
     RECT  9.539 7.872 10.021 10.296 ;
     RECT  10.021 6.096 10.268 10.296 ;
     RECT  9.829 0.528 10.277 4.2 ;
     RECT  10.277 0.432 10.309 4.2 ;
     RECT  10.268 6.048 10.309 10.296 ;
     RECT  10.309 0.432 10.361 10.296 ;
     RECT  10.361 0.528 10.508 10.296 ;
     RECT  9.353 12.048 10.508 12.504 ;
     RECT  10.508 0.528 10.612 12.972 ;
     RECT  10.612 0.528 10.643 12.702 ;
     RECT  10.643 0.576 10.804 12.702 ;
     RECT  10.804 0.576 11.081 1.8 ;
     RECT  10.804 10.32 11.081 10.872 ;
     RECT  10.804 6.864 11.117 8.184 ;
     RECT  11.117 7.728 11.189 8.184 ;
     RECT  10.804 12.048 11.189 12.072 ;
     RECT  10.804 5.664 11.557 5.688 ;
     RECT  11.081 10.848 11.593 10.872 ;
     RECT  10.804 2.784 11.665 4.2 ;
     RECT  11.081 1.104 11.699 1.8 ;
     RECT  11.189 7.728 11.765 7.992 ;
     RECT  11.765 7.968 11.801 7.992 ;
     RECT  11.699 1.68 11.941 1.8 ;
     RECT  11.845 0.096 12.133 0.12 ;
     RECT  11.665 2.88 12.269 4.2 ;
     RECT  12.133 0.096 12.485 0.168 ;
     RECT  12.269 2.88 12.515 3.192 ;
     RECT  12.437 8.544 12.521 8.568 ;
     RECT  11.941 1.68 12.629 1.848 ;
     RECT  12.629 1.728 12.689 1.848 ;
     RECT  12.689 1.728 12.701 2.376 ;
     RECT  12.485 0.144 12.737 0.168 ;
     RECT  12.701 2.304 12.773 2.376 ;
     RECT  12.773 2.352 12.889 2.376 ;
     RECT  12.269 4.176 13.633 4.2 ;
     RECT  13.633 4.176 15.084 4.296 ;
    LAYER M5 ;
     RECT  6.864 0.016 12.84 1.763 ;
     RECT  7.056 1.763 12.84 1.811 ;
     RECT  7.632 1.811 12.84 1.859 ;
     RECT  2.4 2.137 2.52 2.151 ;
     RECT  5.1 2.137 5.22 2.151 ;
     RECT  7.68 1.859 12.84 2.387 ;
     RECT  7.68 2.387 12.504 2.821 ;
     RECT  7.632 2.821 12.504 3.397 ;
     RECT  7.584 3.397 12.504 4.165 ;
     RECT  5.1 2.151 5.412 4.645 ;
     RECT  4.224 4.645 5.412 6.181 ;
     RECT  6.96 4.165 12.504 6.899 ;
     RECT  4.224 6.181 5.544 7.235 ;
     RECT  2.4 2.151 2.712 7.765 ;
     RECT  6.96 6.899 8.112 7.861 ;
     RECT  6.96 7.861 8.232 8.003 ;
     RECT  9.216 6.899 12.504 8.003 ;
     RECT  2.4 7.765 3.048 8.483 ;
     RECT  5.1 7.235 5.544 8.533 ;
     RECT  9.456 8.003 12.504 8.579 ;
     RECT  7.8 8.003 8.232 9.011 ;
     RECT  9.456 8.579 11.544 9.155 ;
     RECT  2.4 8.483 2.712 9.541 ;
     RECT  2.4 9.541 3.432 9.637 ;
     RECT  2.16 9.637 3.432 9.923 ;
     RECT  5.1 8.533 5.736 10.213 ;
     RECT  9.552 9.155 11.544 10.307 ;
     RECT  10.5 10.307 11.544 10.883 ;
     RECT  7.8 9.011 8.112 11.941 ;
     RECT  9.504 11.029 9.528 12.083 ;
     RECT  2.16 9.923 2.712 12.517 ;
     RECT  5.1 10.213 6.312 12.517 ;
     RECT  2.16 12.517 6.312 12.805 ;
     RECT  7.536 11.941 8.112 12.805 ;
     RECT  2.16 12.805 8.112 12.949 ;
     RECT  10.5 10.883 10.812 12.969 ;
     RECT  10.5 12.969 10.62 12.983 ;
     RECT  2.16 12.949 8.232 15.056 ;
  END
END dsfd_rly_63_NS
END LIBRARY
